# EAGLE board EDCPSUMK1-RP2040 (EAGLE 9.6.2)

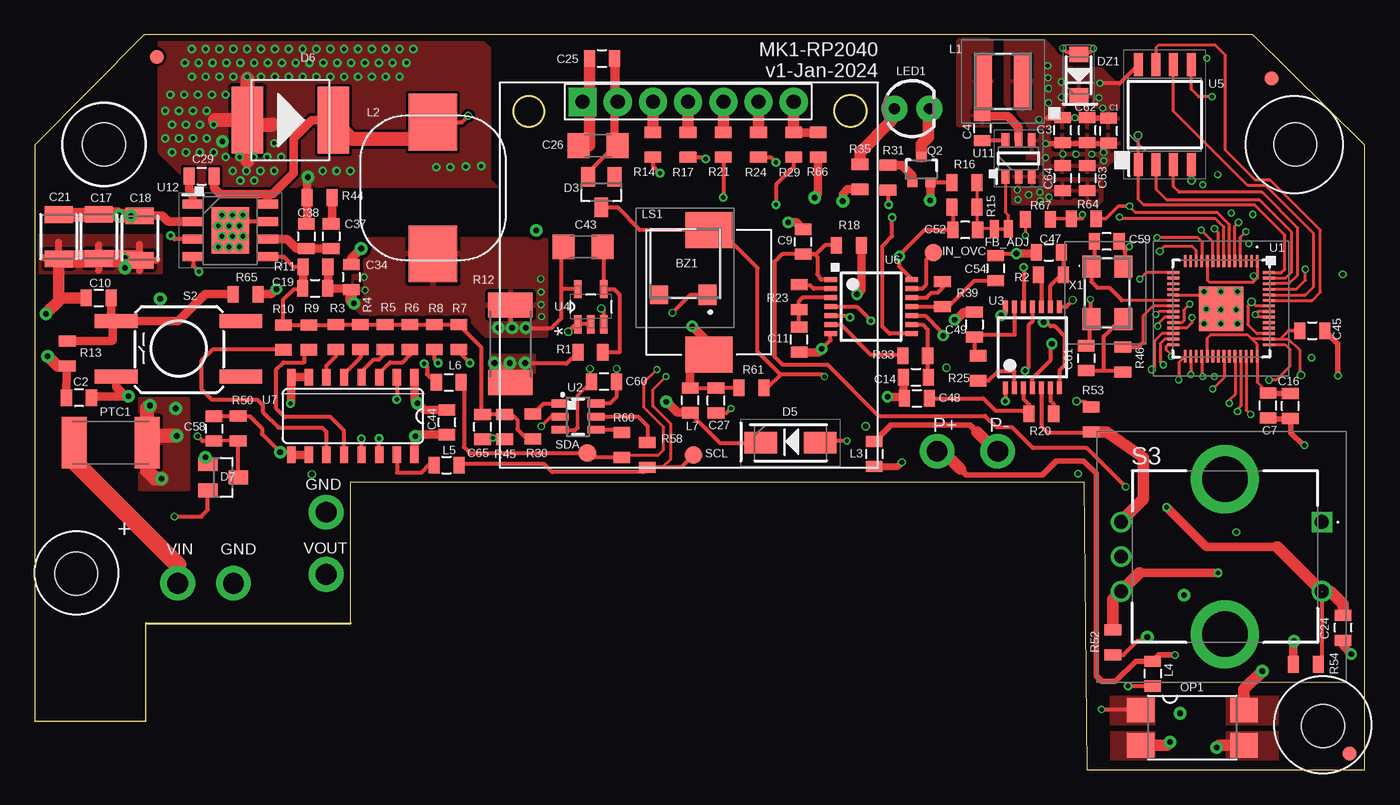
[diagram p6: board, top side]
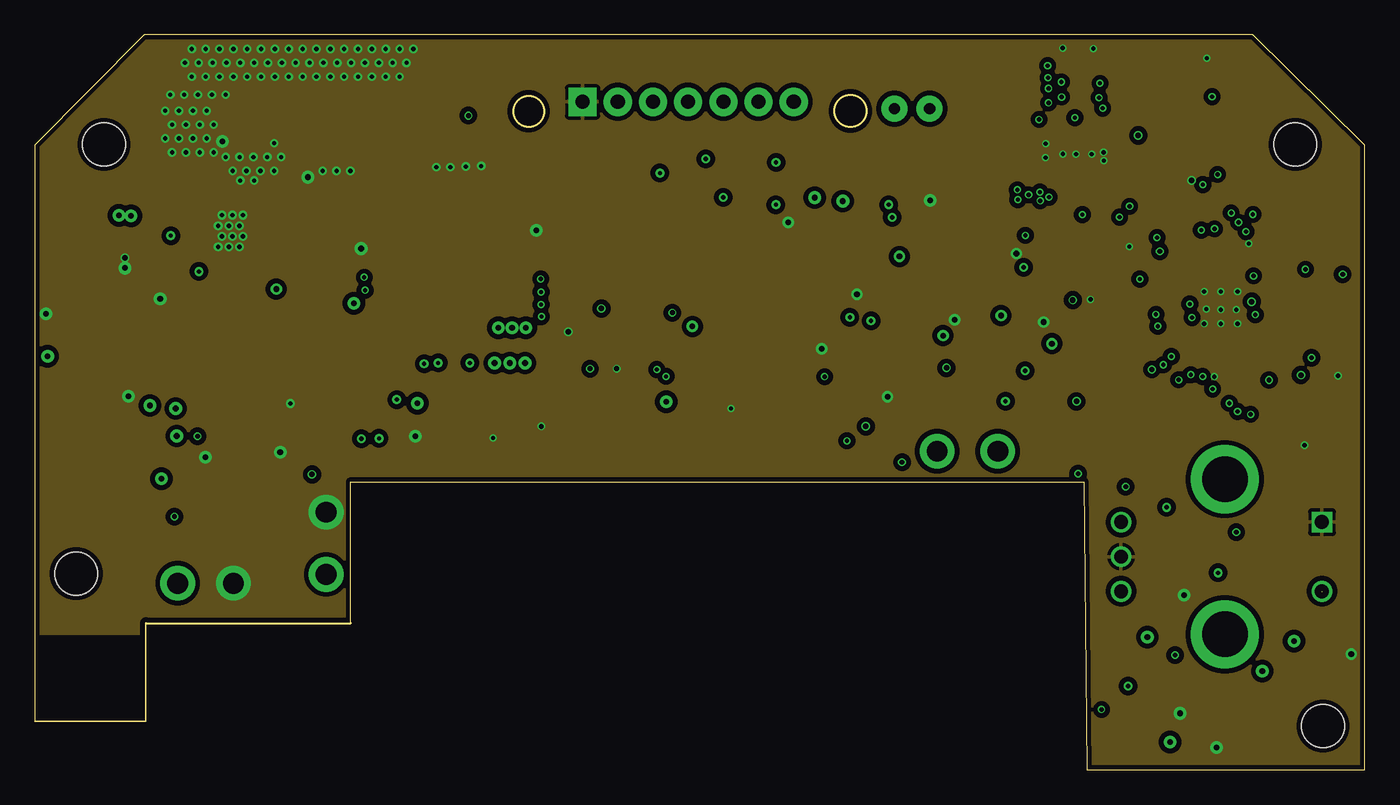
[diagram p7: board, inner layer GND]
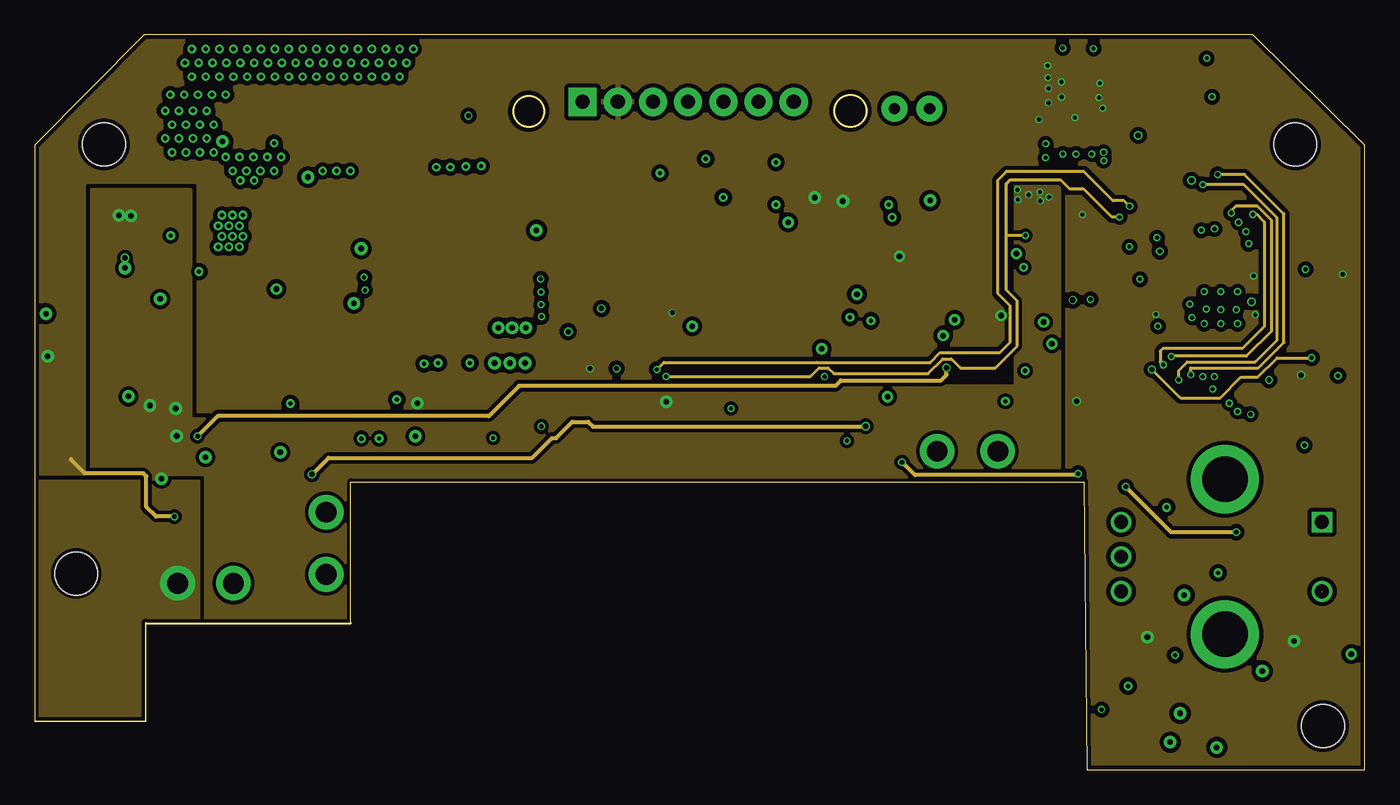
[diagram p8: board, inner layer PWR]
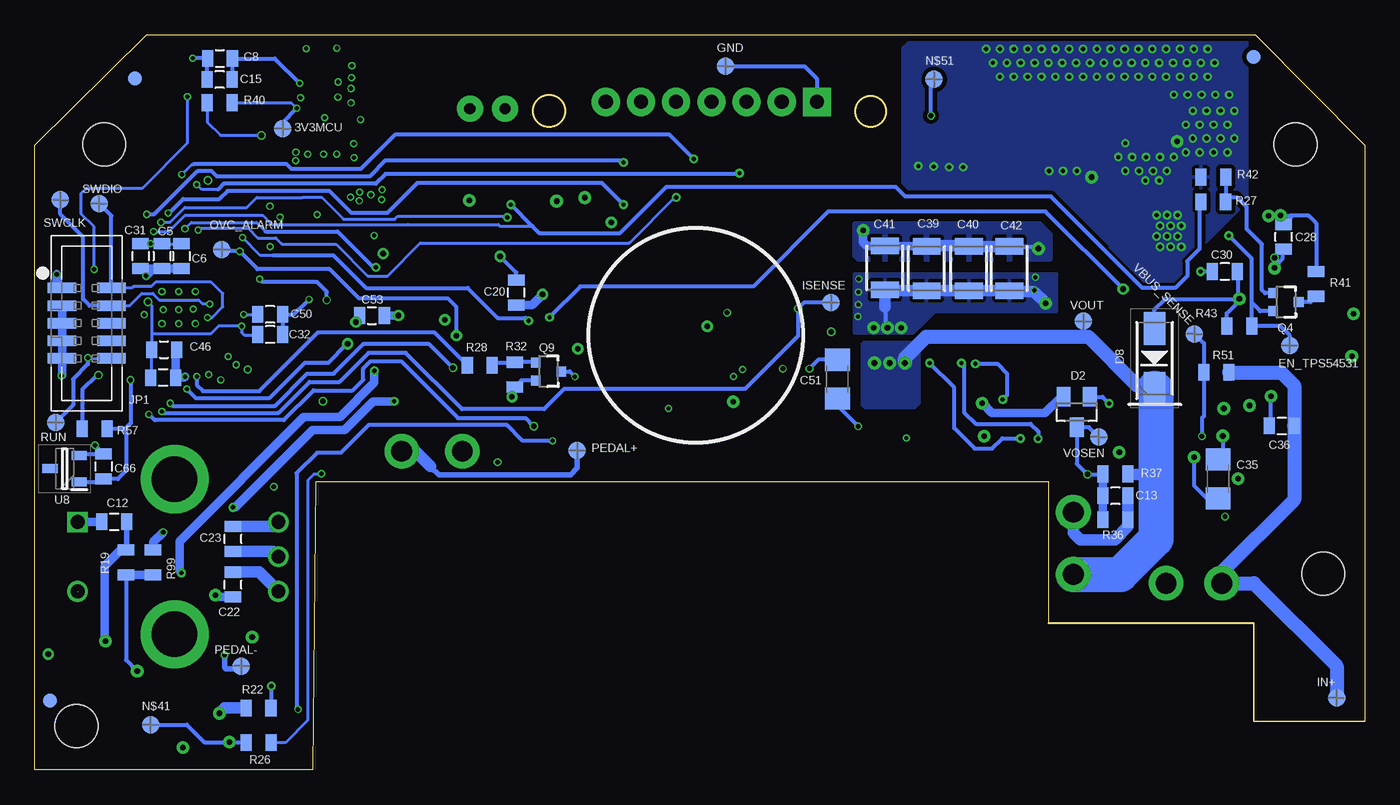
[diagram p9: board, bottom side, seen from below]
Size 96 x 53.1 mm. Coordinates in mm from the lower left corner, seen from the top.
Outline: 96,0 96,45.1 87.9,53.1 7.9,53.1 0,45.1 0,3.5 8,3.5 8,10.6 22.8,10.6 22.8,20.8 75.71,20.8 75.92,0 96,0
Outline: circle at 35.64,47.56 radius 1.09
Outline: circle at 58.87,47.59 radius 1.14
Copper layers (1*2*15*16): Top 0.035mm / dielectric 0.2mm / GND 0.0175mm / dielectric 0.3mm / PWR 0.0175mm / dielectric 0.2mm / Bottom 0.035mm
Design rules "SeeedStudio_4layer_DRU_no_angle_20140221 *": minimum track width 8mil, minimum drill 12mil, track to track 8mil, track to pad 8mil, pad to pad 8mil, via to via 8mil, smd to smd 0mil, copper to edge 10mil, drill to drill 8mil, minimum pad ring 6mil, minimum via ring 4mil, stop-mask expansion 4mil, vias tented up to drill 25mil, thermal gap 10mil
Net classes: 1 vcc: width 0.254 mm
Holes 3.1 mm at 4.98,45.18 90.98,45.18 2.98,14.18 92.98,3.18
tRestrict: area 0.4,11.6 to 5.4,16.6; area 2.5,42.7 to 7.5,47.7; area 88.5,42.7 to 93.5,47.7; area 90.5,0.7 to 95.5,5.7
bRestrict: area 90.5,0.7 to 95.5,5.7; area 88.5,42.7 to 93.5,47.7; area 2.5,42.7 to 7.5,47.7; area 0.4,11.7 to 5.4,16.7

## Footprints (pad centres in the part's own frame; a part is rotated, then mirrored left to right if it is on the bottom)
TESTPAD_B1,27 = smd 1.27 x 1.27: TP 0,0
PKMCS0909 = smd 2.6 x 3.4: 1 -4.5,0; 2 4.5,0
0805 = smd 0.8 x 1.2: 1 -0.9,0; 2 0.9,0
1210 = smd 1.2 x 2: 1 -1.6,0; 2 1.6,0
1206 = smd 1.6 x 1.8: 1 -1.4,0; 2 1.4,0
SOT23 = smd 1 x 1.4: 1 -0.95,-1.1; 2 0.95,-1.1; 3 0,1.1
DIOM5226X244N = smd 2.35 x 1.55: 1 -2.15,0; 2 2.15,0
DO-214AB = smd 2.286 x 4.8: 1 -3.1,0; 2 3.1,0
SODFL3518X115N = smd 1.12 x 1.37: 1 -1.5,0; 2 1.5,0
SMT-JUMPER_2_NC_TRACE_NO-SILK = smd 0.635 x 1.27: 1 -0.508,0; 2 0.508,0
FIDUCIAL-1X2 = smd 1 x 1: 1 0,0
OLED_LCD = drill 1.016 pad 2.032 square: 1 -7.42,13.7 | drill 1.016 pad 2.032: 2 -4.88,13.7; 3 -2.34,13.7; 4 0.2,13.7; 5 2.74,13.7; 6 5.28,13.7; 7 7.82,13.7
20021521-00010T1LF = smd 0.76 x 2.05: 1 -2.54,-1.78; 2 -2.54,1.78; 3 -1.27,-1.78; 4 -1.27,1.78; 5 0,-1.78; 6 0,1.78; 7 1.27,-1.78; 8 1.27,1.78; 9 2.54,-1.78; 10 2.54,1.78
NRS4018T100MDGJ = smd 1.2 x 3.7: 1 -1.4,0; 2 1.4,0
WE-LHMI = smd 4.1 x 3.5: 1 -4.75,0; 2 4.75,0
LED3MM = drill 0.813 pad 1.88: A -1.27,0; K 1.27,0
SMT0540SR = smd 1.5 x 1.3: 1 -2.25,-1.6; 2 2.25,-1.6 | smd 1.3 x 1.3: 3 -2.25,1.9
SMD4 = smd 1.78 x 2: 1 -1.27,-3.725; 2 1.27,-3.725; 3 1.27,3.725; 4 -1.27,3.725
1812L = smd 1.8 x 3.7: 1 -2.6,0; 2 2.65,0
SOT323 = smd 0.7 x 0.7: 1 -0.65,-0.925; 2 0.65,-0.925; 3 0,0.925
R2512 = smd 1.8 x 3.2: 1 -2.8,0; 2 2.8,0
TAC_SW_SMD_KSC931G = smd 3.1 x 1: 1 -4.5,2; 2 4.5,2; 3 -4.5,-2; 4 4.5,-2
PEC12R3220FS0024 = drill 1 pad 1.5 square: 1 0,0 | drill 1 pad 1.5: 2 5,0; A1 0,-14.5; B1 5,-14.5; C1 2.5,-14.5 | drill 3.28 pad 4.92: MH1 -3.1,-7; MH2 8.1,-7
RP2040TR7 = smd 0.875 x 0.2: 1 -3.438,2.6; 2 -3.438,2.2; 3 -3.438,1.8; 4 -3.438,1.4; 5 -3.438,1; 6 -3.438,0.6; 7 -3.438,0.2; 8 -3.438,-0.2; 9 -3.438,-0.6; 10 -3.438,-1; 11 -3.438,-1.4; 12 -3.438,-1.8; 13 -3.438,-2.2; 14 -3.438,-2.6; 29 3.438,-2.6; 30 3.438,-2.2; 31 3.438,-1.8; 32 3.438,-1.4; 33 3.438,-1; 34 3.438,-0.6; 35 3.438,-0.2; 36 3.438,0.2; 37 3.438,0.6; 38 3.438,1; 39 3.438,1.4; 40 3.438,1.8; 41 3.438,2.2; 42 3.438,2.6 | smd 0.2 x 0.875: 15 -2.6,-3.438; 16 -2.2,-3.438; 17 -1.8,-3.438; 18 -1.4,-3.438; 19 -1,-3.438; 20 -0.6,-3.438; 21 -0.2,-3.438; 22 0.2,-3.438; 23 0.6,-3.438; 24 1,-3.438; 25 1.4,-3.438; 26 1.8,-3.438; 27 2.2,-3.438; 28 2.6,-3.438; 43 2.6,3.438; 44 2.2,3.438; 45 1.8,3.438; 46 1.4,3.438; 47 1,3.438; 48 0.6,3.438; 49 0.2,3.438; 50 -0.2,3.438; 51 -0.6,3.438; 52 -1,3.438; 53 -1.4,3.438; 54 -1.8,3.438; 55 -2.2,3.438; 56 -2.6,3.438 | smd 3.2 x 3.2: 57 0,0
SOT23-6 = smd 0.55 x 1.2: 1 0.95,1.3; 2 0,1.3; 3 -0.95,1.3; 4 -0.95,-1.3; 5 0,-1.3; 6 0.95,-1.3
TSSOP14 = smd 0.35 x 0.9: 1 -1.95,-2.925; 2 -1.3,-2.925; 3 -0.65,-2.925; 4 0,-2.925; 5 0.65,-2.925; 6 1.3,-2.925; 7 1.95,-2.925; 8 1.95,2.925; 9 1.3,2.925; 10 0.65,2.925; 11 0,2.925; 12 -0.65,2.925; 13 -1.3,2.925; 14 -1.95,2.925
SOT95P280X145-5N = smd 1.321 x 0.559: 1 -1.27,0.94; 2 -1.27,0; 3 -1.27,-0.94; 4 1.27,-0.94; 5 1.27,0.94
SOIC127P790X216-8N = smd 1.65 x 0.65: 1 -3.6,1.905; 2 -3.6,0.635; 3 -3.6,-0.635; 4 -3.6,-1.905; 5 3.6,-1.905; 6 3.6,-0.635; 7 3.6,0.635; 8 3.6,1.905
SO16 = smd 0.6 x 1.2: 1 -4.445,-2.8; 2 -3.175,-2.8; 3 -1.905,-2.8; 4 -0.635,-2.8; 5 0.635,-2.8; 6 1.905,-2.8; 7 3.175,-2.8; 8 4.445,-2.8; 9 4.445,2.8; 10 3.175,2.8; 11 1.905,2.8; 12 0.635,2.8; 13 -0.635,2.8; 14 -1.905,2.8; 15 -3.175,2.8; 16 -4.445,2.8
SOT96P240X120-3N = smd 1.1 x 0.65: 1 -1.05,0.96; 2 -1.05,-0.96; 3 1.05,0
SOT95P280X100-6N = smd 1.05 x 0.55: 1 -1.3,0.95; 2 -1.3,0; 3 -1.3,-0.95; 4 1.3,-0.95; 5 1.3,0; 6 1.3,0.95
SOIC127P600X163-9N = smd 1.5 x 0.65: 1 -2.7,1.905; 2 -2.7,0.635; 3 -2.7,-0.635; 4 -2.7,-1.905; 5 2.7,-1.905; 6 2.7,-0.635; 7 2.7,0.635; 8 2.7,1.905 | smd 2.71 x 3.35: 9 0,0
ABM3C16000MHZD4YT = smd 1.6 x 1.3: 1 -1.9,-1.15; 2 1.9,-1.15; 3 1.9,1.15; 4 -1.9,1.15

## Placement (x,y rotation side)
3V3MCU  TESTPAD_TPSQB1,27  [TESTPAD_B1,27]  78.11,46.32 0 bottom
BZ1  PKMCS0909E4000-R1  [PKMCS0909]  48.64,34.5 90 top
C1  100n 50v X7R/X5R  [0805]  77.5,46.15 90 top
C2  100n 50v X7R/X5R  [0805]  3.18,26.88 180 top
C3  22uF 10V X5R  [0805]  74.18,46.2 90 top
C4  100n 50v X7R/X5R  [0805]  68.38,46.33 270 top
C5  100n 50v X7R/X5R  [0805]  86.81,37.1 270 bottom
C6  100n 50v X7R/X5R  [0805]  85.4,37.1 270 bottom
C7  100n 50v X7R/X5R  [0805]  89,26.31 90 top
C8  100n 50v X7R/X5R  [0805]  82.62,51.38 0 bottom
C9  1uF 50V X7R  [0805]  55.45,38.14 90 top
C10  100n 50v X7R/X5R  [0805]  4.61,34.08 0 top
C11  1uF 50V X7R  [0805]  55.16,31.09 90 top
C12  100n 50v X7R/X5R  [0805]  90.25,17.93 0 bottom
C13  1uF 50V X7R  [0805]  17.98,19.8 180 bottom
C14  100n 50v X7R/X5R  [0805]  63.6,28.36 0 top
C15  1uF 50V X7R  [0805]  82.65,49.85 180 bottom
C16  100n 50v X7R/X5R  [0805]  90.62,26.29 90 top
C17  4.7uF 50V X7R  [1210]  4.6,38.53 270 top
C18  4.7uF 50V X7R  [1210]  7.56,38.41 270 top
C19  N.C.  [0805]  20.22,34.77 0 top
C20  100n 50v X7R/X5R  [0805]  61.23,34.47 90 bottom
C21  4.7uF 50V X7R  [1210]  1.71,38.5 270 top
C22  100n 50v X7R/X5R  [0805]  81.69,13.39 90 bottom
C23  100n 50v X7R/X5R  [0805]  81.69,16.69 90 bottom
C24  100n 50v X7R/X5R  [0805]  94.44,10.28 90 top
C25  100n 50v X7R/X5R  [0805]  40.93,51.38 0 top
C26  10uF 50V X5R/X7R  [1206]  40.64,45.09 180 top
C27  100n 50v X7R/X5R  [0805]  49.16,26.68 90 top
C28  100n 50v X7R/X5R  [0805]  5.84,38.5 90 bottom
C29  100n 50v X7R/X5R  [0805]  12.03,42.88 0 top
C30  33n  [0805]  10.08,35.99 180 bottom
C31  100n 50v X7R/X5R  [0805]  88.35,37.1 270 bottom
C32  100n 50v X7R/X5R  [0805]  78.99,31.44 180 bottom
C33  100n 50v X7R/X5R  [0805]  86.73,28.33 180 bottom
C34  100n 50v X7R/X5R  [0805]  22.84,35.59 270 top
C35  10uF 50V X5R/X7R  [1206]  10.57,21.01 270 bottom
C36  100n 50v X7R/X5R  [0805]  5.98,24.85 0 bottom
C37  10nF  [0805]  21.38,38.53 270 top
C38  16pF  [0805]  19.59,38.53 270 top
C39  22uF 25V X5R  [1210]  31.61,36.21 90 bottom
C40  22uF 25V X5R  [1210]  28.56,36.21 90 bottom
C41  22uF 25V X5R  [1210]  34.62,36.26 90 bottom
C42  22uF 25V X5R  [1210]  25.64,36.21 90 bottom
C43  10uF 50V X5R/X7R  [1206]  39.56,37.77 0 top
C44  100n 50v X7R/X5R  [0805]  29.75,25.11 90 top
C45  1uF 50V X7R  [0805]  92.2,31.72 0 top
C46  1uF 50V X7R  [0805]  86.66,30.35 0 bottom
C47  100n 50v X7R/X5R  [0805]  73.2,37.39 0 top
C48  100n 50v X7R/X5R  [0805]  63.66,26.83 0 top
C49  100n 50v X7R/X5R  [0805]  67.82,32.16 270 top
C50  100n 50v X7R/X5R  [0805]  79.01,32.89 180 bottom
C51  10uF 50V X5R/X7R  [1206]  38.06,28.22 90 bottom
C52  N.C  [0805]  67.15,38.99 180 top
C53  100n 50v X7R/X5R  [0805]  71.65,32.82 0 bottom
C54  1uF 50V X7R  [0805]  69.35,36.23 270 top
C58  100n 50v X7R/X5R  [0805]  12.93,24.64 270 top
C59  27p  [0805]  77.36,38.16 180 top
C60  100n 50v X7R/X5R  [0805]  41.07,28.04 180 top
C61  27p  [0805]  75.89,29.73 270 top
C62  22uF 10V X5R  [0805]  75.96,46.2 90 top
C63  4.7uF 50V X5R  [0805]  75.96,42.73 270 top
C64  4.7uF 50V X5R  [0805]  74.18,42.74 270 top
C65  N.C.  [0805]  32.31,24.78 90 top
C66  100n 50v X7R/X5R  [0805]  91.02,21.91 270 bottom
D2  BAV199  [SOT23]  20.77,25.84 180 bottom
D3  N.C  [SOT23]  40.88,41.73 180 top
D5  3SMAJ5923B-TP  [DIOM5226X244N]  54.54,23.62 0 top
D6  N.C  [DO-214AB]  18.43,46.92 0 top
D7  BAV199  [SOT23]  13.59,21.13 270 top
D8  RB060M-60TR  [DIOM5226X244N]  15.16,29.73 90 bottom
DZ1  MMSZ5228B-7-F  [SODFL3518X115N]  75.34,50.16 90 top
EN_TPS54531  TESTPAD_TPSQB1,27  [TESTPAD_B1,27]  5.41,30.65 0 bottom
FB_ADJ  JUMPER-SMT_2_NC_TRACE_NO-SILK  [SMT-JUMPER_2_NC_TRACE_NO-SILK]  69.77,39.07 0 top
FID1  FIDUCIAL1X2  [FIDUCIAL-1X2]  89.27,49.94 0 top
FID2  FIDUCIAL1X2  [FIDUCIAL-1X2]  94.9,1.19 0 top
FID3  FIDUCIAL1X2  [FIDUCIAL-1X2]  8.03,51.49 0 bottom
FID4  FIDUCIAL1X2  [FIDUCIAL-1X2]  8.79,51.49 0 top
FID5  FIDUCIAL1X2  [FIDUCIAL-1X2]  88.76,49.94 0 bottom
FID6  FIDUCIAL1X2  [FIDUCIAL-1X2]  94.9,5 0 bottom
GND  TESTPAD_TPSQB1,27  [TESTPAD_B1,27]  46.12,50.8 0 bottom
IN+  TESTPAD_TPSQB1,27  [TESTPAD_B1,27]  2.02,5.21 0 bottom
IN_OVC  TESTPAD_TPSQB1,27  [TESTPAD_B1,27]  64.85,37.35 0 top
ISENSE  TESTPAD_TPSQB1,27  [TESTPAD_B1,27]  38.53,33.74 0 bottom
J6  Display  [OLED_LCD]  46.95,34.54 0 top
JP1  20021521-00010T1LF  [20021521-00010T1LF]  92.24,32.26 270 bottom
L1  NRS4018T4R7MDGJ  [NRS4018T100MDGJ]  69.87,49.72 0 top
L2  4.7uH  [WE-LHMI]  28.73,42.02 270 top
L3  MMZ2012Y202BT000  [0805]  60.59,22.82 270 top
L4  MMZ2012Y202BT000  [0805]  80.69,6.96 270 top
L5  MMZ2012Y202BT000  [0805]  29.7,22.01 0 top
L6  MMZ2012Y202BT000  [0805]  29.87,27.99 0 top
L7  MMZ2012Y202BT000  [0805]  47.3,26.7 90 top
LED1  [LED3MM]  63.31,47.75 0 top
LS1  SMT-0540-S-R  [SMT0540SR]  46.95,36.56 90 top
N$41  TESTPAD_TPSQB1,27  [TESTPAD_B1,27]  87.63,3.27 0 bottom
N$51  TESTPAD_TPSQB1,27  [TESTPAD_B1,27]  31.07,49.87 0 bottom
OP1  LTV816S  [SMD4]  83.54,3.06 270 top
OVC_ALARM  TESTPAD_TPSQB1,27  [TESTPAD_B1,27]  82.5,37.58 0 bottom
PEDAL+  TESTPAD_TPSQB1,27  [TESTPAD_B1,27]  56.83,23.06 0 bottom
PEDAL-  TESTPAD_TPSQB1,27  [TESTPAD_B1,27]  81.08,7.5 0 bottom
PTC1  2A NOM / 3.5A LIM  [1812L]  5.49,23.62 180 top
Q2  2N7002PW  [SOT323]  63.98,43.36 0 top
Q4  2N7002PW  [SOT323]  5.67,33.79 270 bottom
Q9  2N7002PW  [SOT323]  58.91,28.78 270 bottom
R1  10K  [0805]  40.09,30.16 180 top
R2  1K  [0805]  73.34,35.75 0 top
R3  11K  [0805]  21.72,31.25 90 top
R4  5K6  [0805]  23.49,31.25 90 top
R5  2K8  [0805]  25.27,31.25 90 top
R6  1K4  [0805]  27.05,31.25 90 top
R7  180K  [0805]  30.61,31.25 90 top
R8  91K  [0805]  28.83,31.25 90 top
R9  43K  [0805]  19.79,31.24 90 top
R10  22K  [0805]  17.93,31.24 90 top
R11  15K  [0805]  20.25,36.32 0 top
R12  0.025R / 1W  [R2512]  34.32,30.77 270 top
R13  2K2  [0805]  2.33,30.07 270 top
R14  33R  [0805]  44.6,45.14 90 top
R15  0R  [0805]  67.08,40.64 0 top
R16  N.C  [0805]  67.08,42.41 180 top
R17  33R  [0805]  47.14,45.14 90 top
R18  N.C  [0805]  58.75,37.88 180 top
R19  1K  [0805]  89.4,15 90 bottom
R20  1K  [0805]  72.63,25.72 180 top
R21  33R  [0805]  49.68,45.14 90 top
R22  330R  [0805]  79.84,4.47 180 bottom
R23  2K2  [0805]  55.16,34.14 270 top
R24  33R  [0805]  52.22,45.14 90 top
R25  1K  [0805]  68.1,29.01 90 top
R26  330R  [0805]  79.83,1.98 180 bottom
R27  1K  [0805]  10.93,41.02 180 bottom
R28  33R  [0805]  63.87,29.23 0 bottom
R29  33R  [0805]  54.76,45.14 90 top
R30  N.C  [0805]  35.95,24.81 270 top
R31  330R  [0805]  61.57,42.76 90 top
R32  10K  [0805]  61.34,28.54 270 bottom
R33  330R  [0805]  63.54,29.91 0 top
R35  130R  [0805]  59.55,42.82 90 top
R36  27K  [0805]  17.98,18.08 0 bottom
R37  150K  [0805]  17.98,21.37 180 bottom
R39  10K  [0805]  65.51,34.35 270 top
R40  10K  [0805]  82.63,48.18 0 bottom
R41  150K  [0805]  3.49,35.1 90 bottom
R42  10K  [0805]  10.92,42.8 0 bottom
R43  11K  [0805]  9.04,32.06 0 bottom
R44  25K  [0805]  20.54,41.33 0 top
R45  N.C  [0805]  33.9,24.78 90 top
R46  1K  [0805]  78.53,29.65 270 top
R50  56K  [0805]  14.66,24.66 90 top
R51  390K  [0805]  10.69,28.71 180 bottom
R52  2K2  [0805]  77.81,9.2 270 top
R53  2K2  [0805]  76.25,25.31 90 top
R54  2K2  [0805]  91.73,7.63 180 top
R57  330R  [0805]  91.65,24.65 180 bottom
R58  N.C  [0805]  44.21,22.75 90 top
R60  N.C  [0805]  42.35,23.46 90 top
R61  330R  [0805]  51.73,27.6 180 top
R64  2K2  [0805]  75.7,39.8 180 top
R65  33R  [0805]  15.22,34.35 180 top
R66  10K  [0805]  56.53,45.14 90 top
R67  2K2  [0805]  72.4,39.75 0 top
R99  330R  [0805]  87.45,14.98 90 bottom
RUN  TESTPAD_TPSQB1,27  [TESTPAD_B1,27]  94.48,25.1 0 bottom
S2  [TAC_SW_SMD_KSC931G]  10.37,30.4 180 top
S3  PEC12R-3220F-S0024  [PEC12R3220FS0024]  92.9,17.9 270 top
SCL  TESTPAD_TPSQB1,27  [TESTPAD_B1,27]  47.55,22.76 0 top
SDA  TESTPAD_TPSQB1,27  [TESTPAD_B1,27]  39.87,22.88 0 top
SWCLK  TESTPAD_TPSQB1,27  [TESTPAD_B1,27]  94.14,41.19 0 bottom
SWDIO  TESTPAD_TPSQB1,27  [TESTPAD_B1,27]  91.35,40.9 0 bottom
U1  RP2040TR7  [RP2040TR7]  85.62,33.31 270 top
U2  MCP4725  [SOT23-6]  39.2,25.51 90 top
U3  SN74AC14PWR  [TSSOP14]  72.01,30.52 0 top
U4  MAX9938FEUK+T  [SOT95P280X145-5N]  40.13,33.45 90 top
U5  W25Q64JVSSIQ  [SOIC127P790X216-8N]  81.55,47.32 90 top
U6  SN74AC14PWR  [TSSOP14]  60.35,33.45 270 top
U7  TPIC2810D  [SO16]  22.95,25.56 180 top
U8  LM4040C30FTA  [SOT96P240X120-3N]  93.84,21.76 180 bottom
U11  AP63203  [SOT95P280X100-6N]  71,44.16 90 top
U12  AP64501SP-13  [SOIC127P600X163-9N]  14.1,38.96 0 top
VBUS_SENSE  TESTPAD_TPSQB1,27  [TESTPAD_B1,27]  12.27,31.49 0 bottom
VOSEN  TESTPAD_TPSQB1,27  [TESTPAD_B1,27]  19.19,24.05 0 bottom
VOUT  TESTPAD_TPSQB1,27  [TESTPAD_B1,27]  20.29,32.4 0 bottom
X1  ABM3C-12.000MHZ-D4Y-T  [ABM3C16000MHZD4YT]  77.4,34.46 270 top

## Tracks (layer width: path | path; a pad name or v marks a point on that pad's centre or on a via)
1V1MCU  (via drill 0.3, 0.4)
  Top 0.203: U1.23 81.57,32.71 81.06,32.2 v81.06,32.04 | U1.45 88.21,31.51 87.54,32.18 87.54,33.52 v87.83,33.81 88.13,33.51 U1.50
  Bottom 0.203: C32.2 79.91,31.42 80.86,31.42 81.06,31.62 v81.06,32.04 82.73,32.04 83.25,31.52 87.47,31.52 87.5,31.55 | v87.83,33.81 87.54,33.52 87.54,31.59 87.5,31.55 | 87.5,31.55 87.5,30.41 C46.1 87.58,30.33 87.58,28.38 C33.2
3V3MCU  (via drill 0.3, 0.35, 0.4, 0.41 pad 0.81, 0.41 pad 0.91)
  Top 0.203: 89.9,31.11 U1.44 87.85,31.11 | 89.9,31.11 90.49,31.11 91.29,30.31 91.29,28.61 v91.38,28.52 | v40.07,28.98 40.07,28.14 C60.2 | v80.92,32.9 81.13,33.11 U1.22 | R53.2 75.84,26.62 v75.19,26.62 | U1.33 84.62,31.18 84.84,31.4 87.56,31.4 87.85,31.11 | 87.85,31.11 88.22,30.74 U1.42 88.22,28 C7.2 | U1.10 84.62,35.39 84.77,35.24 87.95,35.24 | 87.95,35.24 87.96,35.24 88.23,35.5 U1.1 | v87.96,35.67 87.96,35.25 87.95,35.24 | U1.49 88.26,33.11 88.1,32.95 v88.1,32.87 88.26,32.71 U1.48 | 89.9,31.11 90.51,31.72
  Top 0.254: 39.17,24.72 39.17,27.04 C60.2 | R67.2 73.35,39.8 R64.2 75.6,39.8 v75.6,40.1 | 90.51,31.72 C45.1
  Top 0.305: J6.2 42.07,51.14 C25.2 | 41.83,44.88 C26.1 41.89,45.09 39.93,43.13 D3.2 | 2.28,29.13 R13.2 | U6.14 63.22,35.46 63.22,35.53 62.4,36.36 v62.4,37.08 62.4,37.18 64.21,38.99 C52.2 66.25,40.57 R15.1 | U3.14 70.06,32.95 69.92,32.81 v69.74,32.81 | R52.2 78.58,8.3 79.58,9.31 80.02,9.31 v80.3,9.59 | D7.2 12.48,18.79 12,18.3 v10.07,18.3 | v46.01,33.02 47.28,34.29 48.53,34.29 LS1.1 | U2.3 39.01,24.56 39.17,24.72 | U5.8 78.31,49.58 v76.88,49.58
  Top 0.406: C1.2 73.15,47.05 73.1,47.1 | C16.2 89.03,27.19 C7.2
  Top 0.61: C25.2 41.83,44.88 | 2.28,29.13 C2.2 | R54.2 90.83,9.24 v90.89,9.31 | R35.1 58.67,41.92 58.32,41.58 v58.32,41.07 | R66.1 56.53,41.57 v56.29,41.33 | C44.2 28.08,26.01 v27.6,26.49 27.4,26.69 U7.1 | 90.6,27.21 C16.2
  Top 0.813: R13.2 1.63,29.17 v0.92,29.88
  PWR 0.305: v10.07,18.3 8.75,18.3 8.04,19.01 8.04,21.21 7.83,21.42 3.6,21.42 2.59,22.43
  Bottom 0.203: v80.92,32.9 80.89,32.87 79.89,32.87 C50.2 | R40.2 77.47,48.18 v77.07,47.78
  Bottom 0.305: v62.4,37.08 61.23,35.92 C20.2 | v40.07,28.98 39.43,29.62 C51.2 | v91.38,28.52 91.5,28.52 92.55,27.46 R57.2 | 3V3MCU.TP 78.11,46.74 v77.07,47.78 | v76.88,49.58 78.66,51.36 81.7,51.36 C8.2 81.72,49.88 C15.1
  Bottom 0.406: R19.2 89.34,15.95 C12.2
  Bottom 0.61: D2.2 21.9,26.94 23.06,25.79 26.89,25.79 v27.6,26.49 | C53.2 v69.75,32.82 v69.74,32.81 | v90.89,9.31 90.95,9.37 90.95,14.73 89.78,15.9 R19.2 | v87.96,35.67 87.45,36.19 | 87.45,36.19 C5.2 C6.2 | JP1.1 94.4,35.18 v94.4,35.79 | C31.2 87.45,36.19 | C12.2 89.31,17.89
  other vias: 72.48,46.97 73.17,48.17 74.11,48.59 73.17,49.21 73.13,49.99 73.1,50.85 74.09,49.68 75.07,47.1 76.81,48.55
  pour PWR (isolate 0.305, rank 3): -0.95,21.04 -0.95,45.04 7.21,53.2 91.95,53.2 98.68,46.47 98.68,0.18 74.05,0.18 74.05,42.56 70.2,42.56 70.2,28.49 35.77,28.2 32.88,25.29 11.08,25.58 11.08,41.44 4.17,41.44 3.97,21.04
  pour Top (isolate 0.254): 70.1,52.63 72.91,52.63 74.92,50.62 76.94,50.62 78.16,49.4 78.16,46.38 71.82,46.38 70.1,48.1
3V_REF  (via drill 0.35)
  Top 0.203: U1.43 90.25,30.71 90.57,30.39 90.57,29.14 89.59,28.16 v89.08,28.16
  Bottom 0.305: R57.1 89.62,24.65 89.54,24.57 | 89.54,24.57 89.39,24.42 89.39,21.62 90,21.01 C66.2 91.23,20.8 U8.1 | v89.08,28.16 89.06,28.16 89.06,25.05 89.54,24.57
BUZZ  (via drill 0.3)
  Top 0.203: U1.32 84.24,29.85 84.24,28.46 v84.29,28.41
  Bottom 0.305: R28.1 67.12,31.58 75.56,31.58 79.79,27.35 83.84,27.35 84.29,27.8 v84.29,28.41
CS
  Top 0.305: J6.7
  Top 0.61: R66.2 R29.2
  Top 0.813: R29.2 J6.7
D0
  Top 0.305: J6.3
  Top 0.813: R14.2 J6.3
D1
  Top 0.305: J6.4
  Top 0.813: R17.2 J6.4
DSP_RST  (via drill 0.3, 0.3 pad 0.64)
  Top 0.203: U1.9 85.02,38.15 v84.19,38.98
  Top 0.305: R21.1 49.7,44.22 49.7,41.38 v49.68,41.35
  Bottom 0.203: v84.19,38.98 84.06,39.11 80.57,39.11 79.89,38.42 78.6,38.42 78.2,38.02 78.2,38 78.16,37.96 74.24,37.96 71.95,35.67 70.53,35.67 68.16,38.05 53.07,38.05 49.72,41.39 v49.68,41.35
EN_DCDC  (via drill 0.3, 0.3 pad 0.64)
  Top 0.203: U1.4 87.02,38.46 v87.42,38.86 v87.42,38.87
  Top 0.305: R31.1 61.57,40.87 v61.62,40.82
  Bottom 0.203: v87.42,38.87 86.32,38.87 85.14,40.06 79.54,40.06 78.84,39.36 69.09,39.36 69.07,39.38 62.53,39.38 62.43,39.28 60.09,39.28
  Bottom 0.305: v61.62,40.82 60.09,39.28 59.58,38.78 53.73,38.78 50.39,42.11 33.85,42.11 33.15,41.41 22.64,41.41 16.03,34.8 13.66,34.8 12.8,35.66 12.8,36.73 11.93,37.61 11.93,40.92 R27.2
EN_TPS54531  (via drill 0.3 pad 0.64)
  Top 0.305: U12.3 10.05,38.33 v9.8,38.58
  Bottom 0.305: 8.14,33.75 7.52,33.14 Q4.2 | v9.8,38.58 8.15,36.93 8.15,33.76 8.14,33.75 | 8.14,33.75 R43.2 6.08,32.06 5.41,31.39 EN_TPS54531.TP
FB
  Top 0.203: U11.1 70.05,40.29 70.28,40.06 FB_ADJ.2
FB_DAC
  Top 0.305: R30.1 36.7,26.46 U2.1
GND  (via drill 0.3, 0.3 pad 0.6, 0.3 pad 0.64, 0.35, 0.4, 0.4 pad 0.9, 0.41, 0.41 pad 0.81, 0.41 pad 0.91, 1.5 pad 2.5)
  Top 0.203: U1.19 84.17,34.31 v84.4,34.54 | 90.9,25.41 90.64,25.41 C16.1 | U1.57 85.61,33.3 v85.61,33.23 | U12.9 14,39.06 v14,39.29
  Top 0.254: v36.55,24.81 37.25,25.51 U2.2
  Top 0.305: U6.7 57.42,31.04 v56.79,30.4 | U7.9 18.31,22.95 v17.7,22.95 16.4,24.25 16.4,24.65 15.51,25.56 R50.2 14.63,25.54 C58.1 | C54.1 69.51,37.29 v70.84,37.29 | C48.1 62.76,26.84 62.65,26.95 v61.54,26.95 | 6.75,26.98 v6.76,26.97 6.55,26.97 | C2.1 4.18,26.98 | v12.31,22.57 12.81,22.07 D7.1 | v41.99,28.98 41.99,28.06 C60.1 41.97,26.94 41.5,26.47 U2.6 | R16.2 64.66,42.41 Q2.2 | v74.19,52.13 74.46,51.86 DZ1.2 76.18,51.86 v76.41,52.09 | 1.93,34.08 1.71,33.86 | U12.7 15.47,39.59 v15.01,40.06 | C65.1 32.34,23.91 32.99,23.91 v33.06,23.98 33.8,23.98 R45.1 | C27.1 49.92,25.78 v50.25,26.11 | U3.7 73.95,28.86 74.31,29.21 74.31,31.34 73.61,32.04 73.31,32.04 73.08,32.27 72.88,32.27 v72.81,32.34 | U4.2 U4.1 39.02,32.18 v38.49,31.65 | X1.4 78.67,36.47 78.67,37.45 78.81,37.61 | 78.81,37.61 C59.1 | U5.4 83.45,42.59 v83.48,42.57 | v79,37.79 78.81,37.61 | v76.2,33.98 76.2,32.61 X1.2 76.1,32.41 76.1,30.84 C61.1
  Top 0.406: v72.96,45.22 77.47,45.22 C1.1 77.14,44.89 v77.14,44.6 | C45.2 94.06,30.76 v94.06,28.47 | C16.1 90.65,25.36 | 90.65,25.36 90.65,24.35 91.55,23.45 v91.64,23.45 | C7.1 89.05,25.36 90.65,25.36
  Top 0.508: 1.68,38.09 1.71,38.06 C21.2 1.64,36.97 0.57,36.97 | 4.62,37.9 4.6,37.88 C17.2 4.6,36.09 | C18.2 7.55,36.82 7.55,37.95 | 4.6,36.09 | C18.2 7.56,36.06 7.54,36.04 | C18.2 7.57,36.82 8.82,36.82
  Top 0.61: C38.1 19.63,39.47 19.63,40.48 19.64,40.49 R44.1 19.64,42.74 v19.7,42.81 | v23.55,37.65 22.84,36.94 C34.1 | v95.02,8.36 94.44,8.95 C24.1 | U7.9 U7.10 | v18.44,26.47 18.51,26.53 U7.8 U7.7 | C44.1 27.77,24.21 27.66,24.1 v27.46,24.1 27.4,24.04 U7.16 | J6.1 40.03,48.24 | C11.1 55.19,30.16 56.55,30.16 v56.79,30.4 | C49.1 67.05,33.06 66.49,32.5 v66.38,32.5 | C47.1 72.2,37.29 v70.84,37.29 | v54.38,39.55 54.94,39.55 C9.2 | Q2.2 64.63,41.15 v64.62,41.12 | R18.1 59.65,34.66 v59.33,34.34 | 85.46,1.79 v85.3,1.63 | v61.54,26.95 62.64,26.95 62.7,27.01 C14.1 | 6.75,26.98 4.18,26.98 | 6.55,26.97 5.87,27.66 S2.2 | 90.91,25.4 90.9,25.41 | 89.02,25.39 C7.1
  Top 0.813: C21.2 1.71,33.86 v0.79,32.94 | C26.2 40.03,45.09 C25.1 40.03,48.24 | OP1.3 85.46,1.79 | C10.1 1.93,34.08
  Top 1.016: D6.1 13,46.93 | D6.1 15.33,44 | D6.1 15.33,49.9 | D6.1 15.65,46.6 17.15,46.6
  Top 1.27: C21.2 4.57,36.91 C17.2 7.44,36.93 C18.2
  Bottom 0.203: 85.45,37.94 86.76,37.94 C5.1 v87.62,38.01 C31.1
  Bottom 0.305: v18.44,26.47 18.92,26.94 D2.1 | v12.31,22.57 12.31,20.55 11.37,19.61 C35.2 | C36.1 6.76,24.97 v6.76,26.97 | v9.04,34.01 14.39,34.01 15.16,33.24 D8.2 | C28.1 5.95,37.49 5.95,36.88 6.23,36.6 6.23,36.35 6.4,36.35 v6.5,36.25 | v9.04,34.01 9.16,34.13 9.16,35.97 C30.1 | R43.1 9.94,32.96 9.04,33.86 v9.04,34.01 | C15.2 83.55,51.35 C8.1 v84.58,51.38 v84.59,51.39 | C51.1 37.86,26.72 37.91,26.67 37.91,26.17 v36.55,24.81 | Q9.2 60.86,28.13 R32.2 61.34,27.15 v61.54,26.95 | C32.1 78.11,31.46 C50.1 77.29,32.89 v76.2,33.98 | C42.2 23.71,37.81 v23.55,37.65 | U8.2 92.7,22.81 C66.1 91.64,23.43 v91.64,23.45 | GND.TP 40.42,50.8 39.53,49.91 J6.1
  Bottom 0.61: 31.69,37.89 C39.2 31.63,37.83 35.91,37.83 36.2,38.11 v36.2,38.96 | C53.1 72.55,32.51 72.72,32.34 v72.81,32.34 | C22.1 82.82,12.49 v82.96,12.62 | C20.1 60.11,33.57 v59.33,34.34 | C6.1 85.45,37.94 | 86.58,37.94 86.78,37.96 C5.1 | JP1.3 JP1.5 JP1.7 JP1.9 94.02,28.51 v94.06,28.47 | C46.2 85.83,30.28 C33.1 85.19,28.33 v85.12,28.39 | C12.1 92.88,17.93 S3.1
  Bottom 0.813: C42.2 C40.2 28.61,37.86 31.56,37.86 C39.2 | R22.2 82.28,4.47 v82.66,4.09 | v21.02,18.62 21.02,17.12 20.52,16.62 18.04,16.62 17.08,17.58 R36.2 C13.1 | S3.C1 78.79,15.79 C23.1
  other vias: 13.54,45.39 14.25,40.06 13.49,40.06 13.23,39.29 14.76,39.29 15.01,38.53 14.25,38.53 13.49,38.53 13.23,37.77 14,37.77 14.76,37.77 14.27,43.26 14.77,44.26 15.27,43.26 16.27,43.26 15.77,44.26 16.77,44.26 17.27,43.26 17.77,44.26 17.27,45.26 13.77,44.26 9.77,48.76 10.77,48.76 11.77,48.76 12.77,48.76 20.77,43.26 13.77,48.76 21.77,43.26 22.77,43.26 11.32,52.06 12.32,52.06 13.32,52.06 14.32,52.06 15.32,52.06 16.32,52.06 17.32,52.06 18.32,52.06 19.32,52.06 20.32,52.06 21.32,52.06 22.32,52.06 23.32,52.06 24.32,52.06 25.32,52.06 26.32,52.06 27.32,52.06 15.82,42.56 10.82,51.06 11.82,51.06 12.82,51.06 13.82,51.06 14.82,51.06 15.82,51.06 16.82,51.06 17.82,51.06 18.82,51.06 19.82,51.06 20.82,51.06 21.82,51.06 22.82,51.06 23.82,51.06 24.82,51.06 25.82,51.06 26.82,51.06 14.82,42.56 11.32,50.06 12.32,50.06 13.32,50.06 14.32,50.06 15.32,50.06 16.32,50.06 17.32,50.06 18.32,50.06 19.32,50.06 20.32,50.06 21.32,50.06 22.32,50.06 23.32,50.06 24.32,50.06 25.32,50.06 26.32,50.06 9.4,47.6 10.4,47.6 11.4,47.6 12.4,47.6 9.9,46.6 10.9,46.6 11.9,46.6 12.9,46.6 9.4,45.6 10.4,45.6 11.4,45.6 12.4,45.6 9.9,44.6 10.9,44.6 11.9,44.6 12.9,44.6 28.97,43.53 29.99,43.53 31.11,43.57 32.21,43.61 6.5,36.99 72.95,44.21 74.2,44.48 75.15,44.47 76.28,44.47 77.15,44 85.6,34.54 86.81,34.54 86.71,33.23 86.81,32.22 85.6,32.22 84.4,32.22 84.55,33.28 14.32,13.48
  pour Bottom: 11.94,41.68 11.94,37.62 12.8,36.75 12.8,35.48 13.57,34.72 15.88,34.72 18.34,37.19 18.34,40.26 18.75,40.67 18.75,41.38 18.44,41.68
  pour Top (no thermals): 85.96,2.77 85.96,0.74 89.77,0.74 89.77,2.77
  pour Top: 8.9,52.6 8.9,44.62 11.42,42.1 33.4,42.1 32.9,42.6 32.9,52.1 32.4,52.6
  pour Bottom (isolate 0.305): 8.41,52.6 8.41,41.09 12.9,36.6 18.4,36.6 22.9,41.1 32.9,41.1 33.4,41.6 33.4,52.1 32.9,52.6
  pour GND (isolate 0.35): -1.24,9.85 23.08,9.85 23.08,19.4 74.1,19.4 74.1,-2.7 98.99,-2.7 98.99,45.22 89.91,54.3 6.05,54.3 -1.24,47.01
  pour Top: 0.25,38.56 0.25,35.86 9.22,35.86 9.22,38.64 0.25,38.64 0.25,38.57
  pour Top (isolate 0.305): 71.68,45.87 78.2,45.87 78.2,44.48 76.87,43.15 73.36,43.15 72.37,44.14 71.68,44.14
  pour Bottom (isolate 0.254): 23.44,39.4 36.78,39.4 36.78,37.18 36.48,36.88 22.71,36.88 22.71,38.67
IN+  (via drill 1.5 pad 2.5)
  Top 1.016: v10.3,13.48 10.3,14.81 | PTC1.2 2.83,22.27
  Top 1.27: 10.3,14.81 2.83,22.27
  Bottom 0.305: IN+.TP 2.02,5
  Bottom 1.016: R51.1 6.02,28.71 5.08,27.77 C36.2 5.08,19.51 10.3,14.29 v10.3,13.48 7.99,13.48 2.02,7.51 IN+.TP
  pour PWR (isolate 0.254): -0.6,20.87 -0.6,4.25 11.88,-8.23 11.88,20.87
IN_OVC
  Top 0.305: U6.13 64.05,34.75 64.35,35.05 64.35,36.85 IN_OVC.TP
ISENSE  (via drill 0.3, 0.4)
  Top 0.203: U1.39 87.04,29.85 87.04,26.27 86.81,26.04 v86.81,25.89
  Top 0.305: U4.3 41.06,33.14 v40.89,33.32
  Bottom 0.305: v86.81,25.89 86.71,25.79 78.4,25.79 76.16,28.03 73.99,28.03 71.91,30.11 69.21,30.11 65.16,26.06 59.22,26.06 57.77,27.51 44.72,27.51 40.89,31.34 v40.89,33.32 40.47,33.74 ISENSE.TP
MISO  (via drill 0.3, 0.3 pad 0.64)
  Top 0.203: v81.45,29.26 81.23,29.48 81.23,30.79 81.55,31.11 U1.27
  Top 0.305: R24.1 53.12,44.24 v53.49,43.87
  PWR 0.203: v81.45,29.26 81.23,29.48 81.23,30.24 81.46,30.47 87.18,30.47 88.74,32.03 88.74,39.58 88.2,40.12 v87.92,40.12
  Bottom 0.305: v87.92,40.12 87.37,40.12 84.26,43.23 83.21,43.23 82.84,42.86 71.82,42.86 70.66,44.02 53.64,44.02 v53.49,43.87
MOSI  (via drill 0.3, 0.3 pad 0.64)
  Top 0.203: U1.30 83.44,29.85 v83.44,28.55 v83.43,28.54
  Top 0.305: R17.1 48.3,44.24 v48.41,44.12
  PWR 0.203: v83.43,28.54 83.43,29.03 88.33,29.03 90.15,30.86 90.15,40.15 87.3,43 v85.37,43
  Bottom 0.203: v85.37,43 84.63,43.74 84.52,43.74
  Bottom 0.305: v48.41,44.12 50.16,45.87 69.98,45.87 72.46,43.39 77.45,43.39 77.8,43.74 84.52,43.74
N$1
  Top 0.305: U7.6 21.05,29.2 21.72,29.87 R3.1
N$2
  Top 0.305: U7.5 22.32,28.59 23.49,29.77 R4.1
N$3
  Top 0.305: U7.4 23.59,28.77 24.42,29.6 24.82,29.6 25.22,30 25.22,30.3 R5.1
N$4
  Top 0.305: U7.3 24.86,28.64 25.65,29.43 26.53,29.43 27.05,29.95 R6.1
N$5  (via drill 0.3 pad 0.64)
  Top 0.305: R7.1 30.61,30.18 v31.4,29.39 | U7.14 24.86,23.94 v24.84,23.94
  Bottom 0.305: v31.4,29.39 29.62,27.61 29.62,24.69 28.14,23.21 26.89,23.21 26.16,23.94 v24.84,23.94
N$6
  Top 0.305: J6.6
  Top 0.813: R24.2 J6.6
N$7  (via drill 0.3 pad 0.64)
  Top 0.305: R8.1 28.83,29.67 v29.11,29.39 | U7.13 23.56,22.76 v23.56,23.93
  Bottom 0.305: v29.11,29.39 28.91,29.19 28.91,25.83 28.07,24.99 24.12,24.99 23.56,24.43 v23.56,23.93
N$8
  Top 0.305: U7.12 22.32,24.5 21.34,25.48 18.03,25.48 17.43,26.09 17.43,28.93 17.93,29.43 19.43,29.43 19.43,29.99 R9.1
N$9
  Top 0.305: U7.11 21.05,24.4 20.73,24.72 17.58,24.72 16.45,25.85 16.45,26.35 16.06,26.74 12.76,26.74 12.05,27.46 12.05,29.59 12.81,30.35 R10.1
N$10
  Top 0.305: C43.2 41.06,37.67 U4.4 41.79,34.72 42.18,34.33 42.18,30.16 R1.1
N$11
  Top 0.61: 61.88,47.59 LED1.A
  Top 0.813: R35.2 59.55,44.59 61.88,46.91 61.88,47.59
N$12
  Top 0.813: Q2.3 63.98,45.18 64.48,45.68 64.48,47.66 LED1.K
N$13
  Top 0.305: R33.1 62.57,29.97 60.35,29.97 58.17,32.15 U6.6
N$15
  Top 0.305: U6.12 64.35,34.1 64.72,34.47 65.18,34.47 65.51,34.8 R39.1
N$16  (via drill 0.3)
  Top 0.305: v58.62,23.77 56.84,23.77 D5.2 | v76.99,4.37 79.78,4.37 OP1.1
  Bottom 0.305: v76.99,4.37 77.09,4.47 77.09,21.43 75.62,22.9 73.9,22.9 71.9,24.9 61.9,24.9 60.77,23.77 v58.62,23.77
  pour Top (no thermals): 77.58,5.31 77.58,3.28 80.88,3.28 80.88,5.31
N$17
  Top 0.61: R13.1 5.55,30.97 5.6,31.02 5.6,32.13 S2.4 | C10.2 5.5,32.77 S2.4 | S2.4 10.34,32.4 12.29,34.35 R65.2
N$18
  Top 0.305: U3.9 73.31,34.98 74.08,35.75 R2.2 74.25,37.24 C47.2
N$19
  Top 0.305: 19.35,34.8 C19.1 19.27,34.72 18.7,34.72 17.93,33.96 R10.2 R9.2 21.7,32.14 R3.2 R4.2 R5.2 R6.2 R8.2 R7.2 32.2,30.55 32.2,25.79 C65.2 R45.2 33.92,25.66 34.45,25.66 34.82,25.29 34.82,24.6 35.52,23.91 R30.2 | R11.1 18.67,36.32 17.94,37.06 U12.5
  Top 0.61: R11.1 19.35,34.8
N$20
  Bottom 0.305: Q9.1 59.84,29.44 R32.1 62.76,29.44 R28.2
N$21
  Top 0.61: R31.2 62.59,43.66 63.33,42.92 Q2.1
N$22
  Top 0.305: U3.10 72.65,33.45 72.65,35.55 R2.1
N$23
  Top 0.305: U3.6 73.31,26.65 73.53,26.42 R20.1
N$25
  Top 0.305: U3.2 70.7,28.78 69.49,28.78 68.83,28.12 R25.1
N$26
  Top 0.305: R25.2 67.82,30.19 C49.2 67.98,31.42 70.7,31.42 U3.13
N$28
  Top 0.305: U3.3 71.36,26.8 71.76,26.4 71.76,25.74 R20.2 71.53,25.72 71.33,25.93 69.36,25.93 68.46,26.83 C48.2
N$29
  Top 0.305: C11.2 R23.2 55.16,33.85 55.41,34.1 U6.3
N$31  (via drill 0.3)
  Top 0.203: BZ1.2 48.64,38.9 LS1.2
  Top 0.305: BZ1.2 43.67,39 42.04,40.63 D3.3 | LS1.2 49.59,38.81 52.17,36.23 52.17,30.21 53.81,28.57 56.83,28.57 v57,28.4 56.84,28.56 53.85,28.56 52.89,27.6 R61.1
  Bottom 0.305: Q9.3 57.38,28.78 v57,28.4
N$32  (via drill 0.41 pad 0.81)
  Top 0.305: 47.3,28.65 BZ1.1 | L7.2 49.14,27.6 C27.2 50.81,27.58 R61.2
  Top 0.61: L7.2 47.3,28.65 | v47.45,32.03 48.64,30.84 BZ1.1
N$34
  Top 0.305: U6.2 56.2,34.75 55.98,34.98 55.22,34.98 R23.1
N$35
  Bottom 0.305: R41.1 3.9,33.79 Q4.3
N$37
  Top 0.305: U6.9 64.09,32.15 64.44,31.8 R33.2 64.44,28.42 C14.2
N$38
  Top 0.203: R16.1 R15.2 | R15.2 67.98,39.06 C52.1 | FB_ADJ.1 69.27,39.07 69.25,39.09 67.98,39.09 R15.2
N$39
  Top 0.305: R39.2 65.94,33.45 67.81,35.33 C54.2 | U6.11 R39.2 | R39.2
N$40  (via drill 0.3 pad 0.64)
  Top 0.305: U7.2 26.12,26.75 v26.12,26.74 | L6.1 28.62,28.34 28.54,28.34 28.29,28.58 28.29,29.13 v28.09,29.33
  Bottom 0.305: v28.09,29.33 26.52,29.33 25.81,28.63 25.81,27.05 v26.12,26.74
N$41  (via drill 0.41 pad 0.91)
  Top 0.305: 81.72,1.79 v81.95,2.01
  Top 0.813: OP1.2 81.72,1.79
  Bottom 0.305: R26.2 80.99,2.01 v81.95,2.01 83.76,2.01 85.02,3.27 N$41.TP
  pour Top (no thermals): 77.64,2.77 77.64,0.74 80.88,0.74 80.88,2.77
N$43  (via drill 0.35)
  Top 0.508: L3.2 62.29,21.92 v62.59,22.22
  PWR 0.305: v62.59,22.22 63.52,21.29 75.2,21.29 v75.3,21.39
  Bottom 0.203: v75.3,21.39 75.81,21.39 76.28,20.92 76.28,3.59 77.89,1.98 R26.1
N$44  (via drill 0.3 pad 0.64)
  Top 0.305: v11.84,35.99 11.41,36.42 11.41,37.04 U12.4
  Bottom 0.305: C30.2 v11.84,35.98 v11.84,35.99
N$45
  Top 0.305: U2.5 43.54,25.51 44.21,24.84 R58.2
N$46  (via drill 0.3 pad 0.64)
  Top 0.305: L4.2 v78.92,6.06
  Bottom 0.305: v78.92,6.06 78.94,6.03 R22.1
N$47
  Top 0.61: C29.1 11.13,41.87 11.4,41.61 U12.1
N$48
  Top 0.305: U2.4 42.15,24.56 R60.2
N$51  (via drill 0.35)
  Top 0.305: L2.1 30.82,46.77 v31.29,47.25
  Top 0.61: U12.8 16.8,41.53 16.75,41.58 | 16.75,41.58 17.16,41.58 18.68,43.1 18.68,45.63 19.97,46.92 D6.2 | 16.75,41.58 13.36,41.58 12.93,42.01 C29.2
  Top 1.016: D6.2 22.9,45.55 28.77,45.55 L2.1
  Bottom 0.305: v31.29,47.25 31.29,49.65 N$51.TP
N$52
  Top 0.61: C37.2 C38.2 18.89,37.63 18.2,38.33 U12.6
N$53
  Top 0.61: R44.2 21.44,39.5 C37.1
N$54
  Top 0.305: U7.15 26.12,21.48 27.9,21.48 28.43,22.01 L5.1
N$56
  Top 0.305: U11.6 70.02,45.43 C4.2
N$63
  Top 0.305: X1.3 78.17,32.18 78.17,32.02 77.87,32.02 77.15,31.3 77.15,28.83 | 78.43,28.75 R46.2 78.45,28.83 77.15,28.83 | C61.2 77.15,28.83
N$67
  Top 0.305: 68.4,47.21 C4.1
  Top 0.61: U11.5 71,46.43 70.22,47.21 68.4,47.21
  Top 0.813: L1.1 68.47,47.23 C4.1
  pour Top: 69.06,52.73 69.06,46.52 69.08,46.5 66.64,46.5 66.61,46.53 66.61,52.68 66.71,52.78 68.86,52.78
OVC_ALARM  (via drill 0.35, 0.41 pad 0.81)
  Top 0.203: U1.12 83.82,37.5 83.55,37.78 81.5,37.78 81.2,37.47 v81.2,37.45
  Top 0.305: U6.10 64.26,32.8 65.45,31.62 65.55,31.48 v65.55,31.36
  Bottom 0.305: v65.55,31.36 65.55,33.41 66.2,34.06 72.61,34.06 74.71,36.16 79.91,36.16 v81.2,37.45 82.37,37.45 OVC_ALARM.TP 82.5,37.4
PDL  (via drill 0.35)
  Top 0.305: U6.1 56.76,35.4 56.47,35.8 56.47,37.05 56.28,37.24 C9.1 | R18.2 57.03,37.88 56.35,37.21 55.48,37.21 C9.1 | C9.1 53.94,37.24 53.38,36.68 53.38,29.86 53.97,29.27 57.21,29.27 60.9,25.58 68.59,25.58 69.4,24.76 70.53,24.76 72.04,23.25 75.94,23.25 v78.74,20.45
  PWR 0.305: v86.72,17.17 82.02,17.17 v78.74,20.45
  Bottom 0.61: R99.2 87.44,15.89 87.44,16.45 v86.72,17.17
PEDAL  (via drill 0.41 pad 0.91)
  Top 0.813: OP1.4 87.27,5.81 v88.6,7.14
  Bottom 0.305: v88.6,7.14 89.4,7.94 R19.1
  Bottom 0.61: R19.1 89.38,14.08 R99.1
  pour Top (no thermals): 85.96,5.31 85.96,3.28 89.77,3.28 89.77,5.31
PEDAL+  (via drill 1.5 pad 2.5)
  Top 0.406: L3.1 61.79,24.92 67.5,24.92 68,24.42
  Top 0.813: v69.5,23.02 69.4,23.02 68,24.42
  Bottom 0.406: PEDAL+.TP 56.83,21.8 57.33,21.3 66.82,21.3 67.4,21.88 67.4,21.9
  Bottom 0.813: 67.4,21.9 68.52,23.02 v69.5,23.02
PEDAL-  (via drill 0.35, 1.5 pad 2.5)
  Top 0.406: v82.3,8.3 81.13,8.3 L4.1 79.46,7.86 78,6.4 77,6.4 76.6,6.8 76.6,21.4 75.68,22.32 73.72,22.32 72.72,21.32 67.22,21.32 66.82,21.72
  Top 0.813: 66.82,21.72 65.52,23.02 v65.12,23.02
  Bottom 0.406: v82.3,8.3 82.3,7.4 82.2,7.3 81.28,7.3 PEDAL-.TP
PEDAL_IP  (via drill 0.3, 0.3 pad 0.64)
  Top 0.203: U1.11 84.22,38.17 83.95,38.44 v81,38.44
  Top 0.305: U6.4 59.33,33.45 v60.35,32.44
  Bottom 0.203: 78.77,37.16 79.72,37.16 v81,38.44
  Bottom 0.305: 78.77,37.16 74.43,37.16 72.08,34.81 64.75,34.81 62.58,32.64 60.55,32.64 v60.35,32.44
PUSH  (via drill 0.3 pad 0.64, 0.41 pad 0.81)
  Top 0.305: U6.5 58.71,32.8 v58.83,32.69
  Top 0.61: R65.1 17.06,34.35 v17.43,34.72
  Bottom 0.305: v17.43,34.72 23.03,40.32 38.72,40.32 44.12,34.92 56.6,34.92 v58.83,32.69
PUSH_FILT  (via drill 0.3, 0.3 pad 0.64)
  Top 0.203: U1.5 86.62,39.28 v86.88,39.54
  Top 0.305: U6.8 61.69,31.5 61.16,32.03 61.16,37.82 61.88,38.53 v61.88,39.9
  Bottom 0.203: v86.88,39.54 86.22,39.54 85.15,40.61 80.68,40.61 79.97,41.33 76.67,41.33 76.65,41.35 75.3,41.35 73.71,39.76 70.01,39.76 69.79,39.99 61.96,39.99 v61.88,39.9
QSPI_SCLK
  Top 0.203: U1.52 91.69,34.31 92.3,34.92 92.3,38.74 88.84,42.2 87.56,42.2 82.19,47.57 U5.6
QSPI_SD0  (via drill 0.3)
  Top 0.203: U1.53 91.06,34.71 91.71,35.36 v91.71,36.15 | v84.97,48.61 84,48.61 83.45,49.16 U5.5
  Bottom 0.203: v91.71,36.15 91.71,39.22 92.62,40.13 92.62,41.64 92.23,42.03 88.21,42.03 84.96,45.28 v84.96,48.6 v84.97,48.61
QSPI_SD1
  Top 0.203: U1.55 90.27,35.51 90.71,35.95 90.71,38.86 88.37,41.2 81.67,41.2 80.92,41.95 U5.2
QSPI_SD2
  Top 0.203: U1.54 90.52,35.11 91.13,35.72 91.13,39.17 88.59,41.71 82.6,41.71 82.19,42.12 U5.3
QSPI_SD3
  Top 0.203: U1.51 92.2,33.91 92.79,34.5 92.79,38.97 89.16,42.6 88.07,42.6 85.93,44.74 85.93,51.6 85.19,52.34 81.1,52.34 80.92,52.16 U5.7
QSPI_SS  (via drill 0.4)
  Top 0.203: U1.56 89.98,35.91 90.22,36.15 90.22,38.62 88.05,40.79 80.05,40.79 79.64,41.2 U5.1 v79.64,45.81 v79.64,45.82
  Bottom 0.203: R40.1 83.53,46.77 82.58,45.82 v79.64,45.82
ROTA
  Top 0.305: U3.5 72.66,24.79 73.12,24.32 76.16,24.32 R53.1
  Top 0.813: R53.1 77.35,24.41 80.02,22.56 80.02,19.57 78.4,17.95 S3.A1
  Bottom 0.813: C23.2 79.5,17.59 78.78,17.59 78.71,17.59 S3.A1
ROTA_FILT  (via drill 0.3, 0.41 pad 0.81)
  Top 0.203: v85.01,27.51 85.84,28.34 85.84,29.85 U1.36
  Top 0.305: v73.4,30.78 73.29,30.67 73.29,29.55 72.01,28.27 U3.4
  Bottom 0.305: v73.4,30.78 73.43,30.78 74.81,29.4 76.5,29.4 79.07,26.83 84.34,26.83 v85.01,27.5 v85.01,27.51
ROTB  (via drill 0.3 pad 0.64)
  Top 0.305: U3.11 72.01,32.4 71.73,32.12 71.73,29.07 v71.48,28.83
  Top 0.61: 79.76,14.24 v85.4,14.24
  Top 0.813: R52.1 77.81,12.31 S3.B1 79.74,14.24 79.76,14.24
  Bottom 0.61: v71.48,28.83 71.48,27.96 73.95,25.49 76.57,25.49 85.54,16.52 85.54,14.37 v85.4,14.24
  Bottom 0.813: C22.2 79.79,14.29 S3.B1
ROTB_FILT  (via drill 0.3, 0.4)
  Top 0.203: U1.15 80.23,35.91 v79.76,35.44
  Top 0.305: U3.8 74.47,33.45 74.92,33.9 v74.92,33.93
  Bottom 0.305: v74.92,33.93 74.92,34.53 75.64,35.25 78.9,35.25 79.57,35.25 v79.76,35.44
ROTPUSH  (via drill 0.3 pad 0.64)  (1 unrouted)
  Top 0.305: U3.1 v70.06,26.62 | 92.89,12.87 92.89,8.15 92.63,7.88 R54.1
  Top 0.61: v81.69,18.97 84.54,16.12 89.65,16.12 | v70.06,26.62 v70.05,26.62
  Top 0.813: 89.65,16.12 89.68,16.12 S3.2 93.5,12.9 94.44,11.96 C24.2
  Bottom 0.61: v70.05,26.62 71.55,26.62 73.61,24.56 75.94,24.56 81.54,18.97 v81.69,18.97
RPUSH_FILT  (via drill 0.3, 0.3 pad 0.64)
  Top 0.203: U1.8 85.42,38.81 v85.15,39.08
  Top 0.305: v71.37,36.3 71.37,33.47 U3.12
  Bottom 0.203: 79.33,38.88 79.99,39.54 84.69,39.54 v85.15,39.08
  Bottom 0.305: 79.33,38.88 74.14,38.88 71.55,36.3 v71.37,36.3
RST
  Top 0.305: J6.5
  Top 0.813: R21.2 J6.5
RUN  (via drill 0.35)
  Top 0.203: U1.26 81.34,31.51 80.82,30.99 80.82,29.12 v80.62,28.92
  PWR 0.203: v80.62,28.92 82.68,26.86 85.55,26.86 87.05,28.36 88.26,28.36 89.66,29.76 v92.15,29.76
  Bottom 0.203: v92.15,29.76 92.11,29.72 JP1.10
  Bottom 0.305: v92.15,29.76 92.15,29.3 93.22,28.23 93.22,26.36 RUN.TP
SAFETY_EN_DCDC
  Bottom 0.305: R42.2 R27.1 9.69,41.36 9.21,41.36 8.5,40.65 8.5,39.07 7.4,37.97 7.4,34.66 7.18,34.44 Q4.1
SCK  (via drill 0.3, 0.3 pad 0.64)
  Top 0.203: U1.29 82.56,29.41 v82.56,28.17
  Top 0.305: R14.1 44.6,43.61 v45.11,43.1
  PWR 0.203: v82.56,28.17 82.56,28.84 83.18,29.46 88.08,29.46 89.66,31.04 89.66,39.86 87.25,42.27 v84.3,42.27
  Bottom 0.203: 82.76,41.91 83.94,41.91 v84.3,42.27
  Bottom 0.305: v45.11,43.1 45.18,43.03 70.68,43.03 71.38,42.33 82.34,42.33 82.76,41.91
SCL  (via drill 0.3)
  Top 0.203: 45.28,21.85 45.9,22.47 45.9,24.99 44.61,26.28 44.61,27.47 v45.56,28.42 | U1.7 85.82,39.2 85.21,39.81 78.4,39.81 v78.29,39.92 | R67.1 v71.5,38.6
  Top 0.305: L5.2 30.68,22.09 36.75,22.09 37.33,21.51 43.92,21.51 44.24,21.82 R58.1 45.28,21.85 46.64,21.85 SCL.TP
  PWR 0.203: v45.56,28.42 55.99,28.42 56.6,29.03 57.25,29.03 57.66,28.62 64.46,28.62 65.53,29.69 66.15,29.69 66.81,29.03 69.32,29.03 70.91,30.62 70.91,33.86 70.12,34.66 70.12,38.6 | 70.12,38.6 70.12,42.34 70.39,42.61 74.03,42.61 74.69,41.95 75.71,41.95 77.74,39.92 v78.29,39.92 | v71.5,38.6 70.12,38.6
SDA  (via drill 0.3)
  Top 0.203: R60.1 42.5,22.71 44.97,22.71 45.38,23.12 45.38,24.76 43.98,26.16 43.98,28.01 v44.89,28.92 | v79.02,40.7 79.02,40.67 79.43,40.25 85.36,40.25 86.22,39.39 U1.6
  Top 0.254: R64.1 77.3,39.8 78.2,40.7 v79.02,40.7 | v79.02,40.7
  Top 0.305: L6.2 30.97,27.79 30.97,23.31 31.4,22.88 SDA.TP 39.96,22.88 40.28,22.56 R60.1
  PWR 0.203: v44.89,28.92 45.4,29.43 56.43,29.43 64.63,29.43 65.34,30.14 69.65,30.14 70.4,30.89 70.4,33.5 69.51,34.39 69.51,42.61 70.12,43.22 75.7,43.22 77.82,41.1 78.62,41.1 v79.02,40.7
SS  (via drill 0.3, 0.3 pad 0.64)
  Top 0.203: v82.03,29.85 82.03,29.98 81.64,30.37 81.64,30.59 81.76,30.71 U1.28
  Top 0.305: R29.1 54.76,43.53 53.49,42.26 v53.49,40.83 v53.49,40.82
  PWR 0.203: v82.03,29.85 82.03,29.88 87.46,29.88 89.23,31.65 89.23,39.72 88.2,40.75 86.71,40.75 86.35,40.39 v86.35,40.22
  Bottom 0.305: v53.49,40.82 55.05,42.38 68.39,42.38 70.55,40.22 73.12,40.22 74.71,41.81 82.08,41.81 82.67,41.22 85.29,41.22 86.29,40.22 v86.35,40.22
SWCLK  (via drill 0.3)
  Top 0.203: U1.24 82.82,32.31 82.93,32.42 82.93,33.2 v83.37,33.64
  Bottom 0.203: JP1.4 89.15,33.53 88.26,34.42 87.48,34.42 87,33.94 84.17,33.94 83.92,33.69 83.42,33.69 v83.37,33.64
  Bottom 0.305: JP1.4 92.03,33.53 92.5,34 92.5,38.49 94.14,40.13 SWCLK.TP
SWDIO  (via drill 0.3)
  Top 0.203: v83.53,32.67 83.53,32.3 83.14,31.91 U1.25
  Bottom 0.203: v83.53,32.67 83.2,32.67 82.42,33.45 82.42,34.41 83.24,35.23 87.27,35.23 87.59,34.92 88.86,34.92 88.97,34.8 JP1.2
  Bottom 0.305: JP1.2 90.46,40.02 SWDIO.TP
VBUS_SENSE  (via drill 0.3, 0.35, 0.4)
  Top 0.203: U1.38 86.64,29.85 86.64,27.12 86.22,26.7 v86.22,26.48
  Top 0.305: D7.3 14.68,23.79 R50.1 13,23.81 C58.2 12.09,23.75 v11.73,24.1
  PWR 0.305: v11.73,24.1 13.19,25.56 32.77,25.56 34.94,27.74 57.78,27.74 58.18,28.13 65.4,28.13 65.8,28.53 v65.8,29.03
  Bottom 0.305: v65.8,29.03 67.51,30.74 72.28,30.74 74.4,28.62 76.33,28.62 78.65,26.3 86.04,26.3 v86.22,26.48 | v11.73,24.1 11.73,25.4 11.59,25.54 R51.2 11.59,30.81 VBUS_SENSE.TP
VCC  (via drill 0.3, 0.41 pad 0.9, 0.41 pad 0.91)
  Top 0.305: L7.1 47.3,25.77 49.44,23.62 D5.1 | U11.2 71,42.52
  Top 0.61: L7.1 46.38,25.8 v45.57,26.6 | U12.2 9.63,39.58 9.19,40.03 7.58,40.03 C18.1 | C18.1 | C18.1 v6.94,40.01
  Top 1.016: PTC1.1 8.09,26.11 v8.3,26.32 | v10.23,24.12 8.59,24.12 PTC1.1 | PTC1.1 8.09,21.61 8.67,21.04 v9.13,21.04 | v6.94,40.01 6.91,40.03 v6.05,40.03 5.96,40.13 C17.1 4.57,40.11 C21.1
  Bottom 0.305: C35.1 10.22,22.41 10.22,24.11 v10.23,24.12 | v6.05,40.03 5.34,40.03 5.31,40.02 | 5.31,40.02 5.27,39.97 C28.2 | R41.2 3.49,39.47 4.04,40.02 5.31,40.02
  other vias: 10.16,26.11 71.73,41.53 72.54,41.72 73.2,41.36 70.91,41.89 70.95,41.19 72.56,41.1
  pour Top: 7.52,26.85 11.09,26.85 11.12,26.81 11.12,20.2 7.52,20.2
  pour PWR (isolate 0.254, rank 2): 4.11,10.57 4.11,41.89 11.23,41.89 11.23,25.39 11.28,25.34 32.95,25.34 35.06,27.45 56.56,27.45 56.85,27.74 70.78,27.74 70.78,42.26 73.93,42.26 73.93,10.57
  pour Top: 70.61,43.01 72.8,43.01 73.15,42.66 76.97,42.66 77.01,42.62 77.01,41.13 76.76,40.88 70.6,40.88 70.6,42.99
VO_TPS  (via drill 0.3, 0.41 pad 0.91)
  Top 0.305: R12.1 34.32,32.06 v34.44,31.93 | 21.14,34.8 C19.2 | 22.75,34.78 C34.2 | v35.44,31.93 37.31,31.93 38,32.62 38,34.78 | C43.1 38,37.61 38,34.78 | U4.5 38.06,34.72 38,34.78
  Top 0.61: R11.2 21.14,34.8 | C19.2 22.75,34.78
  Top 0.813: C34.2 22.84,33.88 v23.01,33.71
  Bottom 0.305: C41.1 34.57,34.61 34.57,32.06 v34.44,31.93
  Bottom 0.813: 34.57,34.61 C39.1 C40.1 C42.1 25.64,34.55 23.85,34.55 v23.01,33.71 | C41.1 34.62,33.42
  other vias: 33.44,31.93 36.51,35.46 36.53,34.51 36.54,33.6 36.56,32.74 23.77,35.58 23.83,34.64
  pour Bottom (isolate 0.254): 22.25,35.86 22.25,33.07 31,33.07 32.57,31.5 36.81,31.5 36.81,35.86
  pour Top (isolate 0.254): 23.05,38.28 23.05,33.56 23.62,32.99 31.01,32.99 32.58,31.42 36.85,31.42 36.85,38.28
VOSEN  (via drill 0.3, 0.4)
  Top 0.203: U1.40 87.44,29.85 87.44,25.99 v87.75,25.68
  PWR 0.305: v20,21.34 21.2,22.54 35.89,22.54 37.31,23.97 37.62,23.97 38.78,25.13 39.94,25.13 40.28,24.79 60,24.79 v59.97,24.81
  Bottom 0.305: R37.2 18.93,21.32 19.98,21.32 v20,21.34 20.77,22.11 D2.3 19.88,24.74 VOSEN.TP | v59.97,24.81 60.57,25.41 65.45,25.41 69.56,29.53 71.74,29.53 72.28,28.98 72.28,28.16 73.03,27.41 75.86,27.41 78.01,25.26 87.33,25.26 v87.75,25.68
  Bottom 0.61: R36.1 C13.2 R37.2
VOUT  (via drill 0.41 pad 0.91, 1.5 pad 2.5)
  Top 0.305: R12.2 34.32,28.25 | R1.2 38.37,29.34 35.42,29.34 v35.37,29.39
  Top 0.61: 34.32,28.25 v33.17,29.39
  Bottom 0.305: VOUT.TP 20.29,31.34 20.35,31.28
  Bottom 0.813: D8.1 15.26,27.27 15.26,21.34 17.05,21.34 R37.1
  Bottom 1.016: v33.17,29.39 33.17,29.75 31.64,31.28 20.35,31.28 19.95,31.28 16.44,27.78 15.36,27.78 D8.1
  Bottom 2.54: v21.02,14.12 17.62,14.12 15.06,16.68 15.06,27.48 D8.1
  other vias: 34.27,29.39
  pour Top (isolate 0.406, no thermals): 32.75,30 32.75,28.8 32.88,28.67 36.12,28.67 36.12,30
  pour Bottom (isolate 0.254, no thermals): 35.9,30 32.75,30 32.75,28.9 32.85,28.8 35.85,28.8 35.9,28.85
  pour Bottom: 31.96,30.93 36.18,30.93 36.34,30.77 36.34,26.34 36.09,26.09 32.44,26.09 32.07,26.46 32.07,30.82
XIN
  Top 0.203: U1.20 78.44,33.92
  Top 0.305: C59.2 76.46,36.57 X1.1 76.25,35.25 76.68,34.82 77.54,34.82 78.44,33.92
XOUT
  Top 0.203: U1.21 80.7,33.51 79.98,32.78 79.98,30.85 79.98,30.79
  Top 0.305: R46.1 79.67,30.55 79.98,30.85

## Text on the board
tPlace: MK1-RP2040 / v1-Jan-2024 | P+ | P- | GND | + | VOUT | VIN | GND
